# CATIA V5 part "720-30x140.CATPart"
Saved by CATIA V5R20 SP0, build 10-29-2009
Part number: 720-30x140
Definition: NONE
Nomenclature: 720-30x140
Source: Unknown
Description: 720-30x140
Bounding box of the stored display mesh (mm): x 0 to 140, y -15 to 15, z -15 to 15
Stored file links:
  C:\Users\Utente\Desktop\IO LAVORO\3D X SITO CF\X SITO\720\720-30x140.CATPart

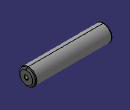
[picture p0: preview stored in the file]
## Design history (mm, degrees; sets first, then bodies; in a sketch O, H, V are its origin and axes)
Body1 "720-30x140" (main body)
  Solid1: solid without history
